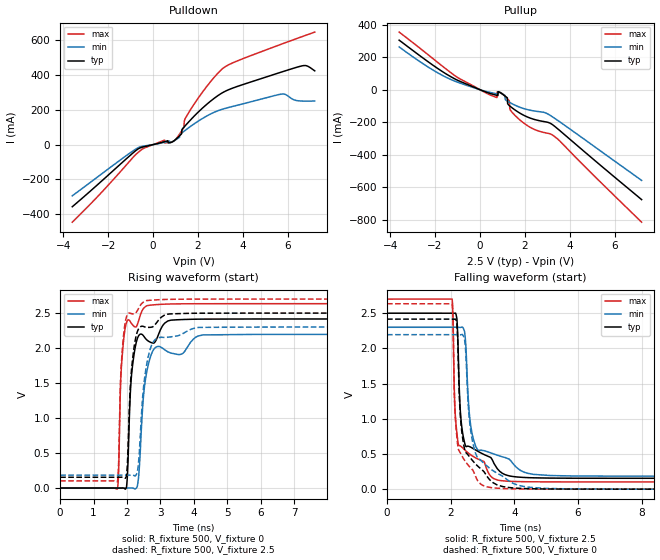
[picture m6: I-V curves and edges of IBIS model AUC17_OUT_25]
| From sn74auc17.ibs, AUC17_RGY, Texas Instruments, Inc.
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[Model]   AUC17_OUT_25
Model_type  Output
Vref =   0
Rref =   500
Cref =   30p
Vmeas =   1.25
| variable   typ   min   max
C_comp   8.23pF   1.92pF   24.88pF
| C_pullup   9.73pF   1.92pF   24.88pF
| C_pulldown   6.74pF   1.95pF   15.98pF
[Temperature Range]   40   100   -40
| Ambient temperature   25   85   -40
[Voltage range]   2.5   2.3   2.7
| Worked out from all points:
|   slope of the pulldown table from 0 to 0.375 V, typ, clamps not added: 30.7 ohm
|   slope of the pullup table from 0 to 0.375 V, typ, clamps not added: 19.1 ohm
|   rising waveform, R_fixture 500, V_fixture 0: 20-80 % time 181ps typ, 247ps min, 134ps max; typ from 0 V to 2.42 V
|   falling waveform, R_fixture 500, V_fixture 2.5: 20-80 % time 229ps typ, 296ps min, 173ps max; typ from 2.5 V to 0.155 V
|   rising waveform, R_fixture 500, V_fixture 2.5: 20-80 % time 184ps typ, 255ps min, 134ps max; typ from 0.154 V to 2.5 V
|   falling waveform, R_fixture 500, V_fixture 0: 20-80 % time 320ps typ, 382ps min, 204ps max; typ from 2.42 V to 0 V
[Pulldown]
| AUC17_OUT_25
|   Voltage   I(typ)   I(min)   I(max)
-3.6V     -357.8mA   -294.9mA   -446.8mA
-560mV    -17.96mA   -12.28mA   -33.37mA
510mV     17.07mA    12.84mA    25.87mA
975mV     26.55mA    25.23mA    25.61mA
1.27V     62.52mA    66.26mA    78.43mA
1.37V     100mA      76.14mA    98.18mA
1.42V     107.2mA    81.05mA    147.2mA
1.85V     166.8mA    121.5mA    237.9mA
3.125V    301.3mA    205.3mA    440.8mA
5.745V    419mA      291.2mA    579.8mA
6.745V    455.4mA    250.4mA    626.9mA
7.2V      424.7mA    251mA      648mA
[Pullup]
| AUC17_OUT_25
|   Voltage   I(typ)   I(min)   I(max)
-3.6V     305mA      263.2mA    354.5mA
-960mV    55.76mA    44.28mA    72.07mA
730mV     -33.82mA   -24.42mA   -47.21mA
760mV     -34.84mA   -25.13mA   -47.16mA
770mV     -35.18mA   -25.36mA   -13.25mA
980mV     -25.02mA   -24.81mA   -22.86mA
1.215V    -49.49mA   -69.56mA   -54.81mA
1.3V      -96.78mA   -76.45mA   -67.02mA
1.34V     -101.5mA   -79.57mA   -121.6mA
1.675V    -135.3mA   -102.3mA   -173.5mA
3.46V     -240.4mA   -188.6mA   -303.3mA
7.2V      -676.1mA   -558mA     -815mA
[Ramp]
| AUC17_OUT_25
| variable   typ   min   max
dV/dt_r   1.46/1.81E-10   1.33/2.47E-10   1.59/1.34E-10
dV/dt_f   1.41/2.29E-10   1.27/2.97E-10   1.56/1.78E-10
R_load = 500
[Rising Waveform]
| AUC17_OUT_25
R_fixture =   500
C_fixture =   0
L_fixture =   0
V_fixture =   0
V_fixture_min = 0
V_fixture_max = 0
|   Time   V(typ)   V(min)   V(max)
0s        13.01nV    39.01nV    2.017nV
1.71ns    -6.455uV   -2.118uV   -14.28mV
1.82ns    292.3uV    -7.376uV   1.625V
1.94ns    -12.55mV   3.614uV    2.269V
2.005ns   122.9mV    104.3uV    2.388V
2.215ns   1.924V     -7.351mV   2.307V
2.345ns   2.173V     147.5mV    2.387V
2.61ns    2.109V     1.704V     2.607V
4.275ns   2.413V     2.188V     2.634V
22ns      2.416V     2.195V     2.634V
[Falling Waveform]
| AUC17_OUT_25
R_fixture =   500
C_fixture =   0
L_fixture =   0
V_fixture =   2.5
V_fixture_min = 2.3
V_fixture_max = 2.7
|   Time   V(typ)   V(min)   V(max)
0s        2.5V       2.3V       2.7V
2.045ns   2.5V       2.3V       2.701V
2.13ns    2.5V       2.3V       1.19V
2.245ns   1.811V     2.299V     629.8mV
2.32ns    1.009V     2.299V     609.3mV
2.465ns   618mV      2.113V     548.2mV
2.58ns    606.6mV    1.106V     504.2mV
2.72ns    573.4mV    699.3mV    461.2mV
3.46ns    293.7mV    483.2mV    131.5mV
22ns      154.5mV    184.4mV    102.7mV
[Rising Waveform]
| AUC17_OUT_25
R_fixture =   500
C_fixture =   0
L_fixture =   0
V_fixture =   2.5
V_fixture_min = 2.3
V_fixture_max = 2.7
|   Time   V(typ)   V(min)   V(max)
0s        154.5mV    184.4mV    102.6mV
1.71ns    154.5mV    184.4mV    89.48mV
1.82ns    154.7mV    184.3mV    1.683V
1.935ns   144.8mV    184.4mV    2.334V
2ns       256.6mV    184.4mV    2.466V
2.21ns    2.004V     179.2mV    2.486V
2.335ns   2.263V     317.3mV    2.557V
2.565ns   2.298V     1.698V     2.676V
4.155ns   2.498V     2.295V     2.699V
22ns      2.5V       2.3V       2.7V
[Falling Waveform]
| AUC17_OUT_25
R_fixture =   500
C_fixture =   0
L_fixture =   0
V_fixture =   0
V_fixture_min = 0
V_fixture_max = 0
|   Time   V(typ)   V(min)   V(max)
0s        2.416V     2.195V     2.634V
2.045ns   2.415V     2.195V     2.634V
2.13ns    2.415V     2.195V     1.149V
2.235ns   1.883V     2.195V     580.4mV
2.305ns   1.032V     2.194V     513.8mV
2.44ns    561.7mV    2.113V     407.7mV
2.665ns   418mV      729.3mV    284mV
3.115ns   201.6mV    338.6mV    35.73mV
4.98ns    2.904mV    10.97mV    822.8uV
22ns      52.8uV     17.98uV    24.14uV
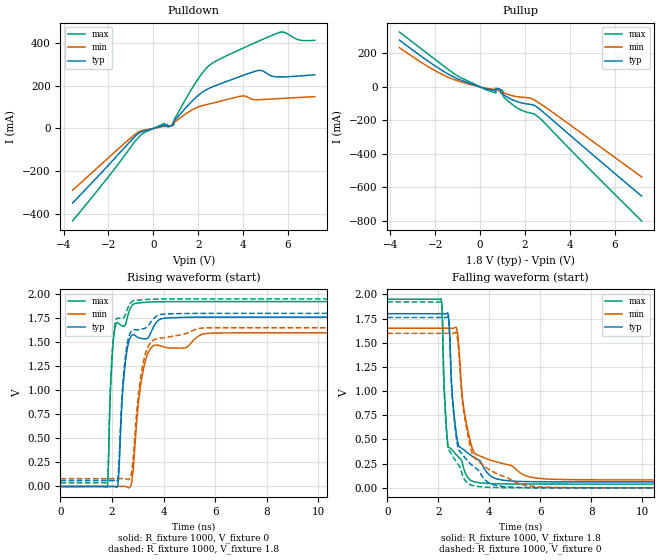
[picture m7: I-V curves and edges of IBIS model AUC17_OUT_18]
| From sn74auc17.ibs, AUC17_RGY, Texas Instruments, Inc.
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[Model]   AUC17_OUT_18
Model_type  Output
Vref =   0
Rref =   1k
Cref =   30p
Vmeas =   0.9
| variable   typ   min   max
C_comp   7.39pF   0.46pF   22.06pF
| C_pullup   8.29pF   1.34pF   22.06pF
| C_pulldown   6.50pF   0.46pF   15.65pF
[Temperature Range]   40   100   -40
| Ambient temperature   25   85   -40
[Voltage range]   1.8   1.65   1.95
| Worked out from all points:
|   slope of the pulldown table from 0 to 0.27 V, typ, clamps not added: 34.3 ohm
|   slope of the pullup table from 0 to 0.27 V, typ, clamps not added: 24.6 ohm
|   rising waveform, R_fixture 1000, V_fixture 0: 20-80 % time 278ps typ, 406ps min, 185ps max; typ from 0 V to 1.76 V
|   falling waveform, R_fixture 1000, V_fixture 1.8: 20-80 % time 454ps typ, 515ps min, 224ps max; typ from 1.8 V to 0.061 V
|   rising waveform, R_fixture 1000, V_fixture 1.8: 20-80 % time 274ps typ, 402ps min, 182ps max; typ from 0.061 V to 1.8 V
|   falling waveform, R_fixture 1000, V_fixture 0: 20-80 % time 457ps typ, 562ps min, 257ps max; typ from 1.76 V to 0 V
[Pulldown]
| AUC17_OUT_18
|   Voltage   I(typ)   I(min)   I(max)
-3.6V     -347.5mA   -287.7mA   -431mA
-555mV    -16.56mA   -10.99mA   -31.53mA
495mV     15.16mA    11.03mA    23.58mA
825mV     12.68mA    12.88mA    14.99mA
925mV     34.89mA    28.34mA    18.72mA
950mV     37.51mA    30.2mA     46.36mA
1.69V     123.2mA    83.99mA    180.4mA
2.535V    189.3mA    115.4mA    296.8mA
3.98V     246.2mA    151.6mA    373.2mA
4.685V    270.1mA    133.9mA    406.2mA
5.665V    240mA      139.4mA    448.2mA
7.2V      250.1mA    148.2mA    410.8mA
[Pullup]
| AUC17_OUT_18
|   Voltage   I(typ)   I(min)   I(max)
-3.6V     279.3mA    234.4mA    328.1mA
-1.27V    65.96mA    49.65mA    89.76mA
375mV     -14.45mA   -9.607mA   -22.05mA
695mV     -22.64mA   -7.581mA   -34.84mA
705mV     -8.525mA   -7.765mA   -10.75mA
835mV     -11.64mA   -24.19mA   -13.09mA
940mV     -38.19mA   -29.59mA   -16.84mA
1.015V    -44.32mA   -33.6mA    -24.07mA
1.045V    -46.82mA   -35.18mA   -57.98mA
1.485V    -78.91mA   -53.64mA   -110mA
2.55V     -121.5mA   -88.73mA   -174.6mA
7.2V      -651.7mA   -536.8mA   -800.1mA
[Ramp]
| AUC17_OUT_18
| variable   typ   min   max
dV/dt_r   1.06/2.81E-10   0.97/4.08E-10   1.16/1.87E-10
dV/dt_f   1.05/4.43E-10   0.95/5.18E-10   1.15/2.25E-10
R_load = 1000
[Rising Waveform]
| AUC17_OUT_18
R_fixture =   1000
C_fixture =   0
L_fixture =   0
V_fixture =   0
V_fixture_min = 0
V_fixture_max = 0
|   Time   V(typ)   V(min)   V(max)
0s        10.21nV    35.63nV    1.217nV
1.82ns    -2.581uV   -818.6nV   -5.146mV
1.955ns   159.2uV    -6.956uV   1.098V
2.1ns     -278.1uV   -16.56uV   1.628V
2.24ns    50.73mV    41.74uV    1.7V
2.55ns    1.358V     -1.57mV    1.708V
2.895ns   1.569V     452.9mV    1.903V
3.465ns   1.576V     1.423V     1.917V
5.54ns    1.76V      1.587V     1.922V
22.5ns    1.761V     1.597V     1.922V
[Falling Waveform]
| AUC17_OUT_18
R_fixture =   1000
C_fixture =   0
L_fixture =   0
V_fixture =   1.8
V_fixture_min = 1.65
V_fixture_max = 1.95
|   Time   V(typ)   V(min)   V(max)
0s        1.8V       1.65V      1.95V
2.115ns   1.8V       1.65V      1.951V
2.23ns    1.8V       1.65V      1.033V
2.385ns   1.795V     1.65V      434.5mV
2.55ns    950.6mV    1.648V     388mV
2.755ns   481.1mV    1.594V     328.9mV
2.98ns    397.4mV    856mV      215.2mV
3.4ns     314.8mV    366mV      63.6mV
6.255ns   62.46mV    91.03mV    39.01mV
22.5ns    61.11mV    81.04mV    38.71mV
[Rising Waveform]
| AUC17_OUT_18
R_fixture =   1000
C_fixture =   0
L_fixture =   0
V_fixture =   1.8
V_fixture_min = 1.65
V_fixture_max = 1.95
|   Time   V(typ)   V(min)   V(max)
0s        61.05mV    81.01mV    38.68mV
1.82ns    61.05mV    81.01mV    35.08mV
1.945ns   61.15mV    81mV       1.079V
2.09ns    61.07mV    81mV       1.649V
2.235ns   110.4mV    81.04mV    1.75V
2.54ns    1.395V     80.46mV    1.802V
2.845ns   1.63V      378.1mV    1.932V
3.415ns   1.675V     1.463V     1.945V
5.375ns   1.799V     1.643V     1.95V
22.5ns    1.8V       1.65V      1.95V
[Falling Waveform]
| AUC17_OUT_18
R_fixture =   1000
C_fixture =   0
L_fixture =   0
V_fixture =   0
V_fixture_min = 0
V_fixture_max = 0
|   Time   V(typ)   V(min)   V(max)
0s        1.761V     1.597V     1.922V
2.115ns   1.761V     1.597V     1.923V
2.23ns    1.761V     1.597V     1.016V
2.38ns    1.761V     1.597V     411.6mV
2.545ns   942.9mV    1.596V     336.4mV
2.735ns   466.2mV    1.569V     258mV
2.97ns    336.2mV    837.9mV    117.9mV
3.29ns    241.9mV    391.5mV    28.48mV
5.815ns   1.983mV    12.93mV    434uV
22.5ns    62.76uV    26.48uV    26.76uV
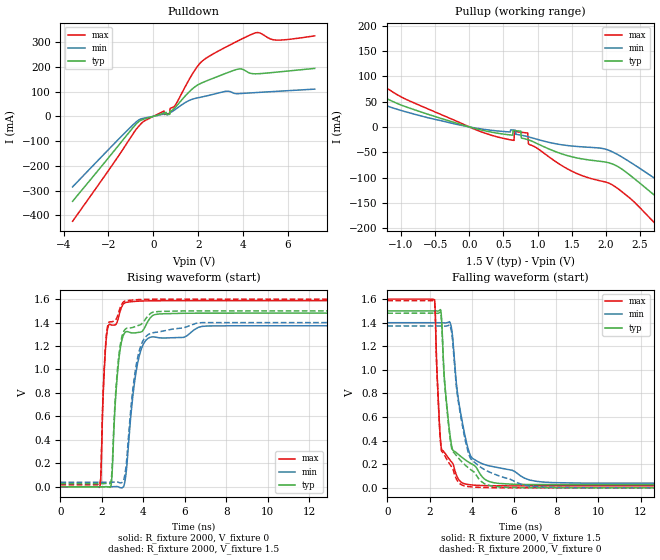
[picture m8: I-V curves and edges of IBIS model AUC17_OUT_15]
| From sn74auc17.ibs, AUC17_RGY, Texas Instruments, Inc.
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[Model]   AUC17_OUT_15
Model_type  Output
Vref =   0
Rref =   2k
Cref =   15p
Vmeas =   0.75
| variable   typ   min   max
C_comp   6.97pF   2.11pF   19.52pF
| C_pullup   6.94pF   2.11pF   19.52pF
| C_pulldown   7.00pF   4.18pF   15.40pF
[Temperature Range]   40   100   -40
| Ambient temperature   25   85   -40
[Voltage range]   1.5   1.4   1.6
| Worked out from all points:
|   slope of the pulldown table from 0 to 0.225 V, typ, clamps not added: 37.3 ohm
|   slope of the pullup table from 0 to 0.225 V, typ, clamps not added: 29.6 ohm
|   rising waveform, R_fixture 2000, V_fixture 0: 20-80 % time 356ps typ, 535ps min, 230ps max; typ from 0 V to 1.48 V
|   falling waveform, R_fixture 2000, V_fixture 1.5: 20-80 % time 469ps typ, 701ps min, 263ps max; typ from 1.5 V to 0.027 V
|   rising waveform, R_fixture 2000, V_fixture 1.5: 20-80 % time 350ps typ, 525ps min, 226ps max; typ from 0.027 V to 1.5 V
|   falling waveform, R_fixture 2000, V_fixture 0: 20-80 % time 540ps typ, 724ps min, 264ps max; typ from 1.48 V to 0 V
[Pulldown]
| AUC17_OUT_15
|   Voltage   I(typ)   I(min)   I(max)
-3.6V     -342.9mA   -284.7mA   -423.6mA
-660mV    -21.86mA   -15.44mA   -41.16mA
480mV     13.54mA    9.64mA     21.5mA
735mV     9.278mA    14.89mA    12.28mA
750mV     20.65mA    15.37mA    31.62mA
980mV     36.14mA    27.9mA     45.24mA
1.79V     114.6mA    70.6mA     177.9mA
2.26V     139mA      80.27mA    228.8mA
3.815V    191.5mA    91.89mA    306.5mA
4.58V     171.9mA    96.07mA    337.7mA
5.485V    178.5mA    100.9mA    308mA
7.2V      193.6mA    110mA      325.1mA
[Pullup]
| AUC17_OUT_15
|   Voltage   I(typ)   I(min)   I(max)
-3.6V     266mA      208.2mA    314.3mA
-2.885V   197.2mA    157.7mA    242.1mA
-2.5V     161mA      126.6mA    203.2mA
-900mV    38.43mA    28.74mA    52.85mA
390mV     -11.89mA   -7.641mA   -18.98mA
855mV     -25.04mA   -19.21mA   -12.06mA
870mV     -25.74mA   -19.76mA   -33.77mA
1.35V     -53.08mA   -35.2mA    -76.07mA
2.13V     -75.14mA   -51.57mA   -117.5mA
2.83V     -148.6mA   -112.3mA   -206.3mA
3.66V     -243.5mA   -190.9mA   -320.6mA
7.2V      -643.6mA   -533mA     -792.5mA
[Ramp]
| AUC17_OUT_15
| variable   typ   min   max
dV/dt_r   0.89/3.56E-10   0.83/5.39E-10   0.96/2.30E-10
dV/dt_f   0.89/4.68E-10   0.82/7.02E-10   0.95/2.63E-10
R_load = 2000
[Rising Waveform]
| AUC17_OUT_15
R_fixture =   2000
C_fixture =   0
L_fixture =   0
V_fixture =   0
V_fixture_min = 0
V_fixture_max = 0
|   Time   V(typ)   V(min)   V(max)
0s        9.392nV    35.9nV     957pV
1.89ns    -5.582uV   -62.32nV   -2.645mV
1.945ns   -9.013uV   -1.389uV   56.89mV
2.175ns   732.6uV    -12.81uV   1.178V
2.415ns   -911.8uV   -12.64uV   1.383V
2.78ns    1.02V      618.6uV    1.428V
3.135ns   1.318V     70.89mV    1.57V
3.675ns   1.314V     1.006V     1.582V
4.31ns    1.435V     1.273V     1.585V
22.2ns    1.481V     1.373V     1.587V
[Falling Waveform]
| AUC17_OUT_15
R_fixture =   2000
C_fixture =   0
L_fixture =   0
V_fixture =   1.5
V_fixture_min = 1.4
V_fixture_max = 1.6
|   Time   V(typ)   V(min)   V(max)
0s        1.5V       1.4V       1.6V
2.24ns    1.5V       1.4V       1.594V
2.37ns    1.499V     1.4V       913.9mV
2.56ns    1.456V     1.4V       334.9mV
2.72ns    889.2mV    1.398V     296.7mV
3.015ns   387.6mV    1.376V     225.2mV
3.585ns   251.4mV    527.4mV    39.68mV
4.035ns   198.9mV    250mV      24.27mV
7.04ns    28.32mV    55.79mV    16.65mV
22.2ns    27.25mV    38.8mV     16.43mV
[Rising Waveform]
| AUC17_OUT_15
R_fixture =   2000
C_fixture =   0
L_fixture =   0
V_fixture =   1.5
V_fixture_min = 1.4
V_fixture_max = 1.6
|   Time   V(typ)   V(min)   V(max)
0s        27.17mV    38.75mV    16.4mV
1.89ns    27.17mV    38.75mV    14.34mV
1.945ns   27.17mV    38.75mV    78.89mV
2.17ns    27.82mV    38.74mV    1.189V
2.405ns   26.96mV    38.72mV    1.407V
2.77ns    1.037V     39.85mV    1.463V
3.12ns    1.342V     113.7mV    1.584V
3.68ns    1.371V     1.06V      1.595V
4.355ns   1.479V     1.308V     1.599V
22.2ns    1.5V       1.4V       1.6V
[Falling Waveform]
| AUC17_OUT_15
R_fixture =   2000
C_fixture =   0
L_fixture =   0
V_fixture =   0
V_fixture_min = 0
V_fixture_max = 0
|   Time   V(typ)   V(min)   V(max)
0s        1.481V     1.373V     1.587V
2.24ns    1.481V     1.373V     1.581V
2.37ns    1.48V      1.373V     904.6mV
2.555ns   1.447V     1.373V     325.6mV
2.705ns   910.4mV    1.371V     277.1mV
2.99ns    395.6mV    1.363V     192.5mV
3.555ns   216.1mV    529.1mV    22.58mV
4.02ns    145.6mV    233.1mV    7.546mV
6.67ns    1.412mV    17.18mV    299.3uV
22.2ns    73.88uV    40.16uV    31.07uV
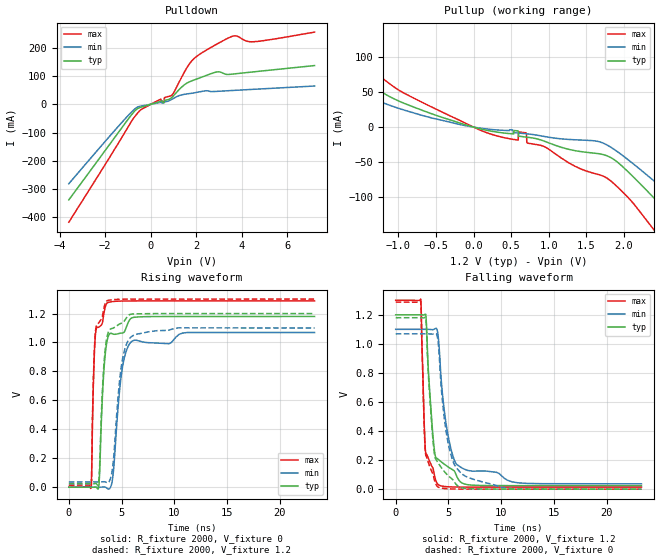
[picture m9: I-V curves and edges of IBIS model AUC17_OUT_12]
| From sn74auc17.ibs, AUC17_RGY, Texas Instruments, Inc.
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[Model]   AUC17_OUT_12
Model_type  Output
Vref =   0
Rref =   2k
Cref =   15p
Vmeas =   0.6
| variable   typ   min   max
C_comp   6.42pF   0.89pF   16.81pF
| C_pullup   6.17pF   0.89pF   16.81pF
| C_pulldown   6.67pF   4.07pF   15.11pF
[Temperature Range]   40   100   -40
| Ambient temperature   25   85   -40
[Voltage range]   1.2   1.1   1.3
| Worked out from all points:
|   slope of the pulldown table from 0 to 0.18 V, typ, clamps not added: 41.6 ohm
|   slope of the pullup table from 0 to 0.18 V, typ, clamps not added: 38.4 ohm
|   rising waveform, R_fixture 2000, V_fixture 0: 20-80 % time 506ps typ, 808ps min, 295ps max; typ from 0 V to 1.18 V
|   falling waveform, R_fixture 2000, V_fixture 1.2: 20-80 % time 683ps typ, 1.14ns min, 340ps max; typ from 1.2 V to 0.024 V
|   rising waveform, R_fixture 2000, V_fixture 1.2: 20-80 % time 495ps typ, 798ps min, 289ps max; typ from 0.024 V to 1.2 V
|   falling waveform, R_fixture 2000, V_fixture 0: 20-80 % time 686ps typ, 1.15ns min, 338ps max; typ from 1.18 V to 0 V
[Pulldown]
| AUC17_OUT_12
|   Voltage   I(typ)   I(min)   I(max)
-3.6V     -338.2mA   -281.1mA   -417.1mA
-650mV    -19.62mA   -13.47mA   -38.35mA
-370mV    -8.898mA   -5.454mA   -16.13mA
590mV     6.193mA    8.413mA    8.677mA
605mV     13.32mA    8.577mA    23.51mA
935mV     25mA       17.89mA    32.75mA
1.62V     76.29mA    36.94mA    133.2mA
2.005V    88.96mA    41.81mA    168.4mA
2.925V    114.6mA    45.74mA    213.8mA
3.635V    107.2mA    49mA       241.6mA
4.51V     114.6mA    52.89mA    221.2mA
7.2V      136.9mA    64.6mA     255.4mA
[Pullup]
| AUC17_OUT_12
|   Voltage   I(typ)   I(min)   I(max)
-3.6V     236.7mA    114.8mA    301.3mA
-2.45V    144.6mA    76.08mA    187.3mA
-2.055V   110.8mA    79.63mA    148.3mA
-675mV    23.63mA    16.44mA    34.85mA
270mV     -6.37mA    -3.622mA   -11.25mA
700mV     -14.19mA   -9.421mA   -8.122mA
715mV     -14.38mA   -9.579mA   -22.55mA
1.785V    -41.22mA   -25.87mA   -73.26mA
2.435V    -104.5mA   -79.46mA   -151mA
2.805V    -145.9mA   -113.4mA   -202mA
3.295V    -201.2mA   -159.3mA   -268.6mA
7.2V      -638.4mA   -533.1mA   -786mA
[Ramp]
| AUC17_OUT_12
| variable   typ   min   max
dV/dt_r   0.72/5.09E-10   0.65/8.13E-10   0.78/2.97E-10
dV/dt_f   0.71/6.86E-10   0.64/1.14E-09   0.78/3.42E-10
R_load = 2000
[Rising Waveform]
| AUC17_OUT_12
R_fixture =   2000
C_fixture =   0
L_fixture =   0
V_fixture =   0
V_fixture_min = 0
V_fixture_max = 0
|   Time   V(typ)   V(min)   V(max)
0s        8.805nV    38.15nV    771.5pV
2.125ns   -8.948uV   169.8nV    2.154mV
2.44ns    755.6uV    -17.52uV   951.2mV
2.8ns     -9.69mV    -36.1uV    1.105V
3.275ns   748.6mV    1.654mV    1.178V
3.635ns   1.014V     -7.135mV   1.273V
4.165ns   1.059V     68.04mV    1.283V
5.095ns   1.066V     833.5mV    1.286V
5.97ns    1.17V      1.008V     1.287V
23.3ns    1.18V      1.069V     1.287V
[Falling Waveform]
| AUC17_OUT_12
R_fixture =   2000
C_fixture =   0
L_fixture =   0
V_fixture =   1.2
V_fixture_min = 1.1
V_fixture_max = 1.3
|   Time   V(typ)   V(min)   V(max)
0s        1.2V       1.1V       1.3V
2.37ns    1.2V       1.1V       1.308V
2.69ns    1.199V     1.1V       484.1mV
2.82ns    1.204V     1.1V       263.4mV
3.55ns    352.6mV    1.098V     140.3mV
4.06ns    203.7mV    1.03V      29.97mV
4.76ns    164.1mV    458.1mV    17.53mV
5.82ns    83.83mV    168.1mV    14.7mV
11.62ns   24.31mV    43.55mV    13.95mV
23.3ns    24.06mV    36.7mV     13.89mV
[Rising Waveform]
| AUC17_OUT_12
R_fixture =   2000
C_fixture =   0
L_fixture =   0
V_fixture =   1.2
V_fixture_min = 1.1
V_fixture_max = 1.3
|   Time   V(typ)   V(min)   V(max)
0s        23.98mV    36.61mV    13.86mV
2.115ns   23.97mV    36.61mV    15.91mV
2.435ns   24.67mV    36.59mV    968mV
2.79ns    20.24mV    36.57mV    1.132V
3.26ns    771.3mV    37.96mV    1.212V
3.605ns   1.032V     32.41mV    1.287V
4.155ns   1.098V     137.1mV    1.296V
5.045ns   1.135V     866.7mV    1.299V
5.975ns   1.196V     1.043V     1.3V
23.3ns    1.2V       1.1V       1.3V
[Falling Waveform]
| AUC17_OUT_12
R_fixture =   2000
C_fixture =   0
L_fixture =   0
V_fixture =   0
V_fixture_min = 0
V_fixture_max = 0
|   Time   V(typ)   V(min)   V(max)
0s        1.18V      1.069V     1.287V
2.37ns    1.18V      1.069V     1.295V
2.69ns    1.179V     1.069V     463.2mV
2.815ns   1.182V     1.069V     251.7mV
3.515ns   351.6mV    1.067V     106.5mV
3.99ns    184.9mV    1.032V     16.45mV
4.425ns   138.5mV    611.4mV    5.926mV
4.92ns    96.71mV    337mV      2.532mV
6.385ns   7.731mV    99.67mV    472.2uV
23.3ns    84.67uV    71.7uV     32.28uV
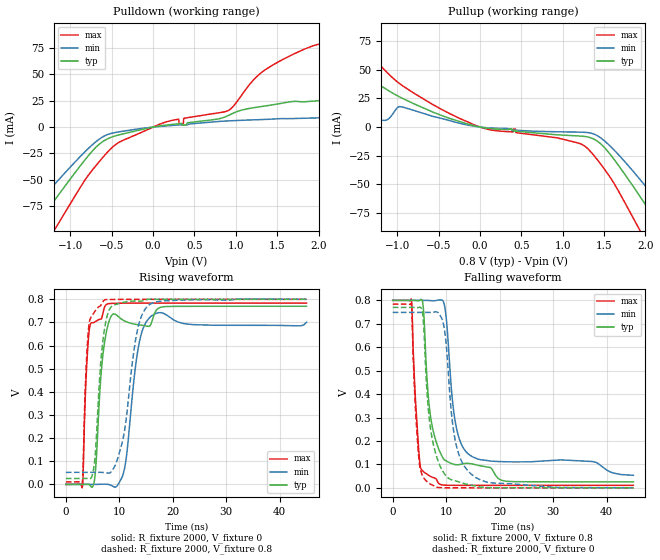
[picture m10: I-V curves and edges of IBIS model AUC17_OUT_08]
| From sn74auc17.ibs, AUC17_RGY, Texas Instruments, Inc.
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[Model]   AUC17_OUT_08
Model_type  Output
Vref =   0
Rref =   2k
Cref =   15p
Vmeas =   0.4
| variable   typ   min   max
C_comp   5.99pF   2.46pF   8.28pF
| C_pullup   5.60pF   2.46pF   8.28pF
| C_pulldown   6.38pF   5.74pF   7.00pF
[Temperature Range]   40   100   -40
| Ambient temperature   25   85   -40
[Voltage range]   0.8   0.8   0.8
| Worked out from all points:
|   slope of the pulldown table from 0 to 0.12 V, typ, clamps not added: 76.3 ohm
|   slope of the pullup table from 0 to 0.12 V, typ, clamps not added: 90.7 ohm
|   rising waveform, R_fixture 2000, V_fixture 0: 20-80 % time 1.44ns typ, 1.9ns min, 863ps max; typ from 0 V to 0.77 V
|   falling waveform, R_fixture 2000, V_fixture 0.8: 20-80 % time 2.34ns typ, 2.27ns min, 1.09ns max; typ from 0.8 V to 0.026 V
|   rising waveform, R_fixture 2000, V_fixture 0.8: 20-80 % time 1.41ns typ, 2.51ns min, 802ps max; typ from 0.025 V to 0.8 V
|   falling waveform, R_fixture 2000, V_fixture 0: 20-80 % time 1.99ns typ, 2.22ns min, 1.04ns max; typ from 0.77 V to 0 V
[Pulldown]
| AUC17_OUT_08
|   Voltage   I(typ)   I(min)   I(max)
-3.6V     -331.8mA   -277.4mA   -406.3mA
-1.795V   -134.9mA   -108.7mA   -175.9mA
-1.39V    -90.86mA   -71.97mA   -123.5mA
-1.17V    -67.18mA   -52.49mA   -94.82mA
-685mV    -18.68mA   -13.51mA   -36.05mA
-430mV    -7.788mA   -4.786mA   -15.33mA
165mV     1.975mA    1.123mA    5.083mA
905mV     10.84mA    5.845mA    15.55mA
1.325V    19.67mA    7.158mA    52.65mA
2.005V    25.02mA    8.764mA    78.63mA
3.33V     32.89mA    11.63mA    90.2mA
7.2V      56.63mA    21.09mA    140.6mA
[Pullup]
| AUC17_OUT_08
|   Voltage   I(typ)   I(min)   I(max)
-3.6V     112.9mA    15.55mA    196mA
-2.87V    85.32mA    16.95mA    166.7mA
-2.085V   45.92mA    22.85mA    129.7mA
-1.6V     30.18mA    13.75mA    86.86mA
-1.305V   39.84mA    7.536mA    62.02mA
-960mV    25.93mA    17.8mA     37.34mA
-370mV    7.654mA    5.694mA    11.92mA
1.35V     -9.645mA   -5.447mA   -22.45mA
1.86V     -52.64mA   -39.33mA   -80.47mA
2.1V      -78.37mA   -60.12mA   -112.5mA
2.385V    -109.5mA   -85.66mA   -150.5mA
7.2V      -640.2mA   -540.3mA   -778mA
[Ramp]
| AUC17_OUT_08
| variable   typ   min   max
dV/dt_r   0.47/1.45E-09   0.45/2.13E-09   0.48/8.65E-10
dV/dt_f   0.47/2.33E-09   0.45/2.26E-09   0.48/1.09E-09
R_load = 2000
[Rising Waveform]
| AUC17_OUT_08
R_fixture =   2000
C_fixture =   0
L_fixture =   0
V_fixture =   0
V_fixture_min = 0
V_fixture_max = 0
|   Time   V(typ)   V(min)   V(max)
0s        10.85nV    62.38nV    582.1pV
3.095ns   -43.72uV   -4.558uV   -11.38mV
4.13ns    775.8uV    -20.3uV    601.4mV
5.25ns    6.134mV    -12.73uV   700mV
6.605ns   482.6mV    667.2uV    715.2mV
7.57ns    658.3mV    671uV      777.7mV
10.8ns    708.6mV    50.72mV    783.3mV
13.53ns   689.9mV    589.3mV    783.5mV
15.94ns   693.6mV    727mV      783.6mV
45ns      770mV      700.7mV    783.7mV
[Falling Waveform]
| AUC17_OUT_08
R_fixture =   2000
C_fixture =   0
L_fixture =   0
V_fixture =   0.8
V_fixture_min = 0.8
V_fixture_max = 0.8
|   Time   V(typ)   V(min)   V(max)
0s        800mV      800mV      800mV
3.5ns     800mV      800mV      802.3mV
4.34ns    799.6mV    800mV      342.8mV
5.54ns    798.7mV    800mV      74.02mV
6.865ns   340.9mV    799.3mV    51.51mV
8.7ns     159.6mV    802mV      16.49mV
9.865ns   116.8mV    752.6mV    11.42mV
11.78ns   98.92mV    270.4mV    10.86mV
14.06ns   104.6mV    145.6mV    10.75mV
45ns      25.56mV    53.52mV    10.62mV
[Rising Waveform]
| AUC17_OUT_08
R_fixture =   2000
C_fixture =   0
L_fixture =   0
V_fixture =   0.8
V_fixture_min = 0.8
V_fixture_max = 0.8
|   Time   V(typ)   V(min)   V(max)
0s        25.46mV    51.93mV    10.6mV
3.075ns   25.44mV    51.93mV    8.79mV
4ns       25.72mV    51.93mV    596mV
4.945ns   39.77mV    51.97mV    730.7mV
5.47ns    120.8mV    52.01mV    749.5mV
7.15ns    660.1mV    50.97mV    795.7mV
10.45ns   785mV      173.9mV    799.6mV
13.25ns   792.4mV    651.3mV    799.8mV
15.45ns   800.2mV    773.7mV    799.8mV
45ns      800mV      800.2mV    800mV
[Falling Waveform]
| AUC17_OUT_08
R_fixture =   2000
C_fixture =   0
L_fixture =   0
V_fixture =   0
V_fixture_min = 0
V_fixture_max = 0
|   Time   V(typ)   V(min)   V(max)
0s        770mV      748.6mV    783.8mV
3.47ns    770mV      748.6mV    785.9mV
4.16ns    769.9mV    748.6mV    378.5mV
4.91ns    770.2mV    748.6mV    120.2mV
5.66ns    730.4mV    748.6mV    47.52mV
6.76ns    310.1mV    748.5mV    20.02mV
9.4ns     69.28mV    707.3mV    562.1uV
11.6ns    30.25mV    212.8mV    217uV
14.59ns   11.55mV    60.11mV    120.3uV
45ns      73.63uV    56.31uV    21.11uV
